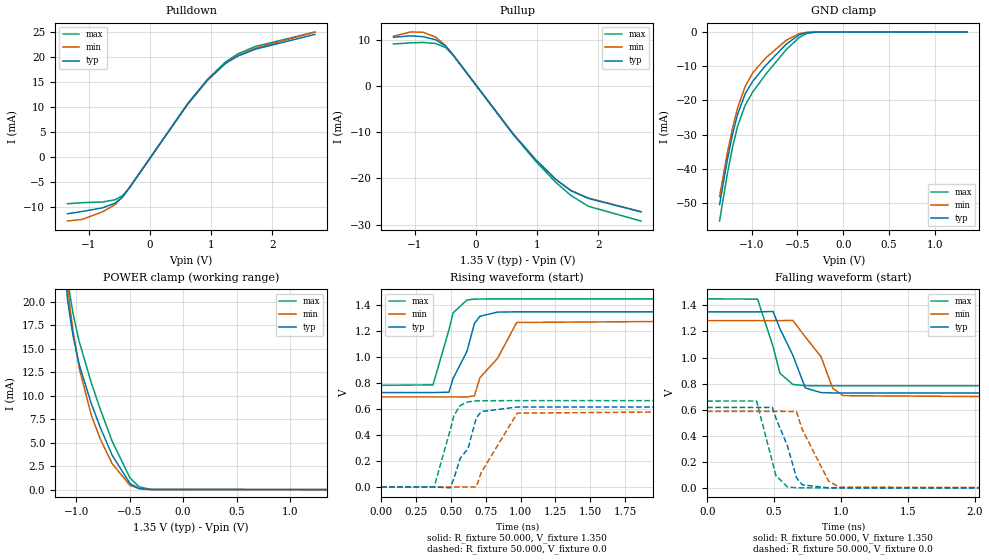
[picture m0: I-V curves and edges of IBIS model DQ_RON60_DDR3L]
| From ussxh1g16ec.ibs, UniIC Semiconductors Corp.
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|   Model DQ_RON60_DDR3L
[Model] DQ_RON60_DDR3L
Model_type I/O
Vinl =  0.540V
Vinh =  0.810V
Vmeas =  0.675V
Rref =  50.000
Vref =  0.675V
C_comp   1.224pF   1.223pF   1.239pF
[Model Spec]
Vinh   0.810V   0.776V   0.860V
Vinl   0.540V   0.506V   0.590V
Vmeas   0.675V   0.641V   0.725V
Vref   0.675V   0.641V   0.725V
Rref   50.000   NA   NA
[Temperature Range]   25.000   95.000   0.0
[Voltage Range]   1.350V   1.283V   1.450V
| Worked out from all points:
|   slope of the pulldown table from 0 to 0.203 V, typ, clamps not added: 55.3 ohm
|   slope of the pullup table from 0 to 0.203 V, typ, clamps not added: 56.9 ohm
|   GND clamp passes 1 mA (typ) near -0.49 V on its own axis
|   POWER clamp passes 1 mA (typ) near -0.53 V on its own axis
|   rising waveform, R_fixture 50.000, V_fixture 1.350: 20-80 % time 138ps typ, 185ps min, 108ps max; typ from 0.728 V to 1.35 V
|   rising waveform, R_fixture 50.000, V_fixture 0.0: 20-80 % time 132ps typ, 176ps min, 106ps max; typ from 0 V to 0.617 V
|   falling waveform, R_fixture 50.000, V_fixture 1.350: 20-80 % time 140ps typ, 184ps min, 112ps max; typ from 1.35 V to 0.728 V
|   falling waveform, R_fixture 50.000, V_fixture 0.0: 20-80 % time 129ps typ, 172ps min, 102ps max; typ from 0.617 V to 0 V
[Pulldown]
|Voltage   I(typ)   I(min)   I(max)
-1.35V    -11.32mA   -12.77mA   -9.304mA
-1.104V   -10.85mA   -12.43mA   -9.089mA
-776mV    -10.13mA   -10.93mA   -8.962mA
-571mV    -9.195mA   -9.485mA   -8.51mA
-448mV    -7.97mA    -7.94mA    -7.687mA
-325mV    -5.951mA   -5.848mA   -5.943mA
618mV     10.72mA    10.58mA    10.76mA
946mV     15.57mA    15.46mA    15.67mA
1.233V    18.79mA    18.79mA    19.06mA
1.438V    20.27mA    20.37mA    20.72mA
1.725V    21.65mA    21.85mA    22.2mA
2.7V      24.61mA    25.09mA    25.08mA
[Pullup]
|Voltage   I(typ)   I(min)   I(max)
-1.35V    10.58mA    10.79mA    9.127mA
-1.072V   10.88mA    11.71mA    9.364mA
-867mV    10.71mA    11.67mA    9.453mA
-662mV    10.05mA    10.62mA    9.234mA
-498mV    8.669mA    8.808mA    8.342mA
-375mV    6.743mA    6.763mA    6.718mA
609mV     -10.37mA   -10.35mA   -10.49mA
978mV     -15.98mA   -15.95mA   -16.28mA
1.306V    -20.22mA   -20.19mA   -20.83mA
1.552V    -22.64mA   -22.59mA   -23.67mA
1.839V    -24.32mA   -24.24mA   -26.02mA
2.7V      -27.24mA   -27.18mA   -29.21mA
[GND_clamp]
|Voltage   I(typ)   I(min)   I(max)
-1.35V    -50.46mA   -48.12mA   -55.26mA
-1.266V   -37.47mA   -35.5mA    -41.62mA
-1.21V    -30.09mA   -28.26mA   -33.85mA
-1.154V   -24.12mA   -22.27mA   -27.6mA
-1.07V    -18.03mA   -15.85mA   -21.35mA
-986mV    -14.32mA   -11.87mA   -17.45mA
-846mV    -9.744mA   -7.556mA   -12.34mA
-622mV    -3.532mA   -2.404mA   -5.117mA
-482mV    -818.9uA   -469.6uA   -1.603mA
-398mV    -151.1uA   -90.66uA   -406.2uA
-286mV    -6.358uA   -5.844uA   -20.22uA
1.35V     0A         0A         0A
[POWER_clamp]
|Voltage   I(typ)   I(min)   I(max)
-1.35V    60.76mA    63.05mA    63.71mA
-1.086V   20.55mA    21.97mA    22.81mA
-1.058V   18.21mA    19.18mA    20.54mA
-1.03V    16.29mA    16.77mA    18.67mA
-974mV    13.34mA    12.95mA    15.78mA
-862mV    9.205mA    7.993mA    11.44mA
-778mV    6.661mA    5.422mA    8.61mA
-666mV    3.683mA    2.783mA    5.175mA
-498mV    635.5uA    452.4uA    1.24mA
-414mV    119.3uA    100.7uA    293.8uA
-302mV    5.933uA    8.44uA     15.23uA
1.35V     0A         0A         0A
[Ramp]
| variable   typ   min   max
dV/dt_r   0.370/0.132n   0.352/0.176n   0.399/0.106n
dV/dt_f   0.373/0.140n   0.353/0.184n   0.400/0.112n
R_load = 50.000
[Rising Waveform]
R_fixture= 50.000
V_fixture= 1.350
V_fixture_min= 1.283
V_fixture_max= 1.450
|time   V(typ)   V(min)   V(max)
0s        727.9mV    694.2mV    783.2mV
372ps     727.9mV    694.2mV    787.2mV
486ps     730.6mV    694.2mV    1.21V
516ps     836.3mV    694.3mV    1.342V
615ps     1.044V     693.8mV    1.441V
669ps     1.26V      702.7mV    1.448V
708ps     1.316V     841.9mV    1.449V
835ps     1.348V     991.8mV    1.45V
972ps     1.35V      1.268V     1.45V
3ns       1.35V      1.283V     1.45V
[Rising Waveform]
R_fixture= 50.000
V_fixture= 0.0
V_fixture_min= 0.0
V_fixture_max= 0.0
|time   V(typ)   V(min)   V(max)
0s        129nV      580.1nV    215nV
380ps     -21.31uV   6.969uV    -8.933uV
495ps     -6.806mV   288.3nV    437.4mV
522ps     65.64mV    -19.91uV   550.9mV
567ps     221.1mV    101.6uV    628.1mV
623ps     295.3mV    419.1uV    656mV
682ps     531.8mV    -149.2uV   663.3mV
718ps     581mV      112.2mV    664.7mV
976ps     616.5mV    569.2mV    665.7mV
3ns       616.6mV    586.6mV    665.7mV
[Falling Waveform]
R_fixture= 50.000
V_fixture= 1.350
V_fixture_min= 1.283
V_fixture_max= 1.450
|time   V(typ)   V(min)   V(max)
0s        1.35V      1.283V     1.45V
377ps     1.35V      1.283V     1.448V
493ps     1.353V     1.283V     1.082V
544ps     1.221V     1.283V     879.3mV
640ps     1.019V     1.285V     793.5mV
734ps     766.1mV    1.158V     784.3mV
852ps     730.8mV    1.005V     783.3mV
938ps     728.4mV    764.5mV    783.2mV
1.018ns   728mV      707.3mV    783.2mV
3ns       727.9mV    694.2mV    783.2mV
[Falling Waveform]
R_fixture= 50.000
V_fixture= 0.0
V_fixture_min= 0.0
V_fixture_max= 0.0
|time   V(typ)   V(min)   V(max)
0s        616.6mV    586.6mV    665.7mV
369ps     616.6mV    586.6mV    666.4mV
487ps     617.3mV    586.6mV    200.8mV
514ps     534.5mV    586.6mV    93.93mV
600ps     322.3mV    586.6mV    7.097mV
668ps     77.81mV    583.8mV    894.8uV
710ps     23.2mV     450mV      248.9uV
908ps     65.67uV    51.07mV    997.6nV
991ps     5.847uV    5.241mV    472.2nV
3ns       294.5nV    649.8nV    404.2nV
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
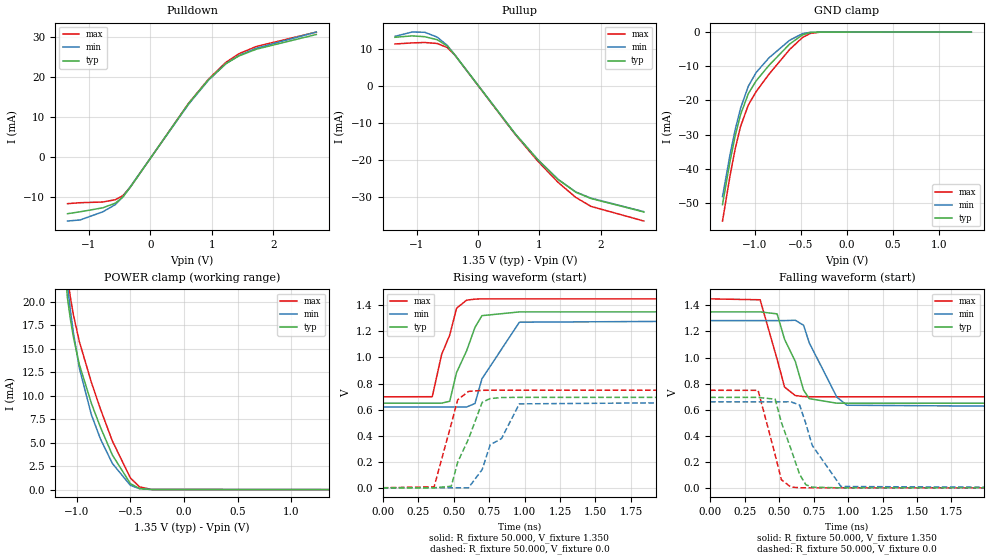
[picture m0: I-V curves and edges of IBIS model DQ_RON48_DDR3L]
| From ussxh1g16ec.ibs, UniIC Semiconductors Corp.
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|   Model DQ_RON48_DDR3L
[Model] DQ_RON48_DDR3L
Model_type I/O
Vinl =  0.540V
Vinh =  0.810V
Vmeas =  0.675V
Rref =  50.000
Vref =  0.675V
C_comp   1.224pF   1.223pF   1.239pF
[Model Spec]
Vinh   0.810V   0.776V   0.860V
Vinl   0.540V   0.506V   0.590V
Vmeas   0.675V   0.641V   0.725V
Vref   0.675V   0.641V   0.725V
Rref   50.000   NA   NA
[Temperature Range]   25.000   95.000   0.0
[Voltage Range]   1.350V   1.283V   1.450V
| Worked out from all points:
|   slope of the pulldown table from 0 to 0.203 V, typ, clamps not added: 44.3 ohm
|   slope of the pullup table from 0 to 0.203 V, typ, clamps not added: 45.6 ohm
|   GND clamp passes 1 mA (typ) near -0.49 V on its own axis
|   POWER clamp passes 1 mA (typ) near -0.53 V on its own axis
|   rising waveform, R_fixture 50.000, V_fixture 1.350: 20-80 % time 140ps typ, 190ps min, 109ps max; typ from 0.649 V to 1.35 V
|   rising waveform, R_fixture 50.000, V_fixture 0.0: 20-80 % time 136ps typ, 182ps min, 107ps max; typ from 0 V to 0.694 V
|   falling waveform, R_fixture 50.000, V_fixture 1.350: 20-80 % time 141ps typ, 188ps min, 111ps max; typ from 1.35 V to 0.649 V
|   falling waveform, R_fixture 50.000, V_fixture 0.0: 20-80 % time 132ps typ, 178ps min, 102ps max; typ from 0.694 V to 0 V
[Pulldown]
|Voltage   I(typ)   I(min)   I(max)
-1.35V    -14.13mA   -15.96mA   -11.62mA
-1.145V   -13.65mA   -15.7mA    -11.38mA
-776mV    -12.66mA   -13.66mA   -11.2mA
-571mV    -11.49mA   -11.85mA   -10.63mA
-448mV    -9.956mA   -9.918mA   -9.604mA
-325mV    -7.433mA   -7.305mA   -7.423mA
618mV     13.39mA    13.21mA    13.45mA
946mV     19.45mA    19.31mA    19.57mA
1.233V    23.48mA    23.48mA    23.82mA
1.438V    25.33mA    25.45mA    25.89mA
1.725V    27.05mA    27.3mA     27.73mA
2.7V      30.73mA    31.34mA    31.32mA
[Pullup]
|Voltage   I(typ)   I(min)   I(max)
-1.35V    13.22mA    13.48mA    11.41mA
-1.072V   13.6mA     14.64mA    11.7mA
-867mV    13.38mA    14.58mA    11.81mA
-662mV    12.56mA    13.26mA    11.54mA
-498mV    10.83mA    11mA       10.42mA
-375mV    8.421mA    8.445mA    8.39mA
609mV     -12.94mA   -12.92mA   -13.1mA
978mV     -19.95mA   -19.92mA   -20.33mA
1.306V    -25.26mA   -25.21mA   -26.02mA
1.593V    -28.67mA   -28.6mA    -30.07mA
1.839V    -30.36mA   -30.26mA   -32.49mA
2.7V      -34mA      -33.92mA   -36.45mA
[GND_clamp]
|Voltage   I(typ)   I(min)   I(max)
-1.35V    -50.46mA   -48.12mA   -55.26mA
-1.266V   -37.47mA   -35.5mA    -41.62mA
-1.21V    -30.09mA   -28.26mA   -33.85mA
-1.154V   -24.12mA   -22.27mA   -27.6mA
-1.07V    -18.03mA   -15.85mA   -21.35mA
-986mV    -14.32mA   -11.87mA   -17.45mA
-846mV    -9.744mA   -7.556mA   -12.34mA
-622mV    -3.532mA   -2.404mA   -5.117mA
-482mV    -818.9uA   -469.6uA   -1.603mA
-398mV    -151.1uA   -90.66uA   -406.2uA
-286mV    -6.358uA   -5.844uA   -20.22uA
1.35V     0A         0A         0A
[POWER_clamp]
|Voltage   I(typ)   I(min)   I(max)
-1.35V    60.76mA    63.05mA    63.71mA
-1.086V   20.55mA    21.97mA    22.81mA
-1.058V   18.21mA    19.18mA    20.54mA
-1.03V    16.29mA    16.77mA    18.67mA
-974mV    13.34mA    12.95mA    15.78mA
-862mV    9.205mA    7.993mA    11.44mA
-778mV    6.661mA    5.422mA    8.61mA
-666mV    3.683mA    2.783mA    5.175mA
-498mV    635.5uA    452.4uA    1.24mA
-414mV    119.3uA    100.7uA    293.8uA
-302mV    5.933uA    8.44uA     15.23uA
1.35V     0A         0A         0A
[Ramp]
| variable   typ   min   max
dV/dt_r   0.416/0.135n   0.396/0.182n   0.449/0.107n
dV/dt_f   0.420/0.141n   0.398/0.187n   0.451/0.111n
R_load = 50.000
[Rising Waveform]
R_fixture= 50.000
V_fixture= 1.350
V_fixture_min= 1.283
V_fixture_max= 1.450
|time   V(typ)   V(min)   V(max)
0s        649.3mV    620.2mV    698.3mV
350ps     649.3mV    620.2mV    698.9mV
416ps     649.5mV    620.2mV    1.023V
473ps     664mV      620.2mV    1.172V
521ps     883.8mV    620.3mV    1.378V
592ps     1.051V     619.8mV    1.44V
651ps     1.231V     646.6mV    1.448V
700ps     1.321V     836.4mV    1.45V
964ps     1.35V      1.271V     1.45V
3ns       1.35V      1.283V     1.45V
[Rising Waveform]
R_fixture= 50.000
V_fixture= 0.0
V_fixture_min= 0.0
V_fixture_max= 0.0
|time   V(typ)   V(min)   V(max)
0s        115.5nV    519nV      192.4nV
363ps     -23.09uV   7.135uV    7.2mV
484ps     11.36mV    -4.386uV   489.9mV
529ps     195.8mV    10.29uV    675mV
605ps     373.4mV    -694.1uV   739.3mV
702ps     656.5mV    140.4mV    748mV
758ps     684.8mV    330.5mV    748.6mV
838ps     692.6mV    377.4mV    748.7mV
963ps     694mV      644mV      748.7mV
3ns       694mV      660mV      748.7mV
[Falling Waveform]
R_fixture= 50.000
V_fixture= 1.350
V_fixture_min= 1.283
V_fixture_max= 1.450
|time   V(typ)   V(min)   V(max)
0s        1.35V      1.283V     1.45V
363ps     1.35V      1.283V     1.443V
486ps     1.335V     1.283V     987.2mV
540ps     1.14V      1.283V     773.2mV
618ps     969.4mV    1.286V     708.1mV
678ps     749.3mV    1.247V     700.4mV
719ps     684.3mV    1.113V     699mV
919ps     649.6mV    696.1mV    698.3mV
992ps     649.3mV    633.9mV    698.3mV
3ns       649.3mV    620.2mV    698.3mV
[Falling Waveform]
R_fixture= 50.000
V_fixture= 0.0
V_fixture_min= 0.0
V_fixture_max= 0.0
|time   V(typ)   V(min)   V(max)
0s        694mV      660mV      748.7mV
348ps     694mV      660mV      748mV
472ps     680.1mV    660mV      252.4mV
517ps     501.6mV    659.9mV    62.21mV
585ps     302mV      660.3mV    6.263mV
649ps     103.7mV    635.7mV    687.5uV
694ps     24.33mV    493.2mV    146.6uV
741ps     5.176mV    325.1mV    28.71uV
949ps     5.542uV    10.33mV    366.5nV
3ns       236nV      593.6nV    311.5nV
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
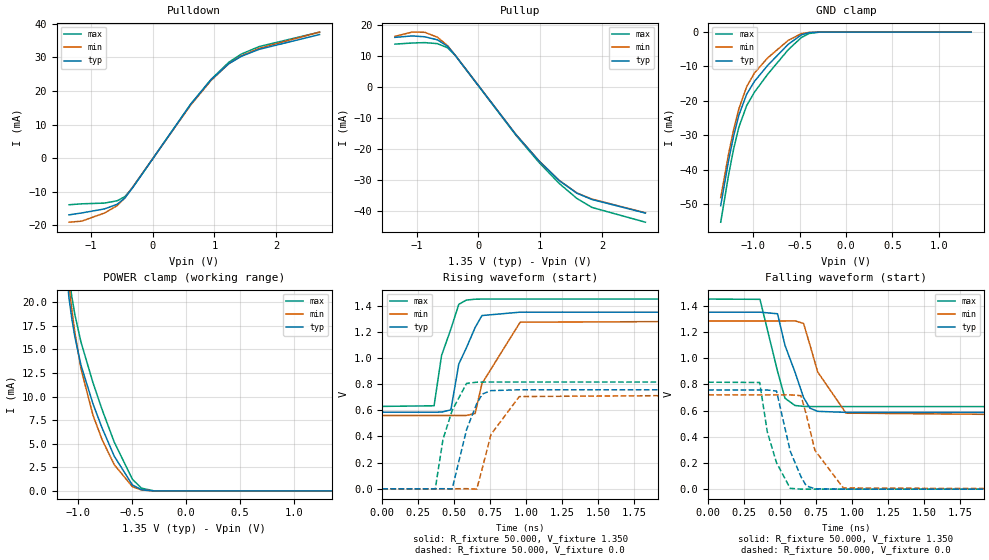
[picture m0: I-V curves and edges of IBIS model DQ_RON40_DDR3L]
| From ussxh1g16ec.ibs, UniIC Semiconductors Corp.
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|   Model DQ_RON40_DDR3L
[Model] DQ_RON40_DDR3L
Model_type I/O
Vinl =  0.540V
Vinh =  0.810V
Vmeas =  0.675V
Rref =  50.000
Vref =  0.675V
C_comp   1.224pF   1.223pF   1.239pF
[Model Spec]
Vinh   0.810V   0.776V   0.860V
Vinl   0.540V   0.506V   0.590V
Vmeas   0.675V   0.641V   0.725V
Vref   0.675V   0.641V   0.725V
Rref   50.000   NA   NA
[Temperature Range]   25.000   95.000   0.0
[Voltage Range]   1.350V   1.283V   1.450V
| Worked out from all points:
|   slope of the pulldown table from 0 to 0.203 V, typ, clamps not added: 36.9 ohm
|   slope of the pullup table from 0 to 0.203 V, typ, clamps not added: 38 ohm
|   GND clamp passes 1 mA (typ) near -0.49 V on its own axis
|   POWER clamp passes 1 mA (typ) near -0.53 V on its own axis
|   rising waveform, R_fixture 50.000, V_fixture 1.350: 20-80 % time 135ps typ, 187ps min, 104ps max; typ from 0.586 V to 1.35 V
|   rising waveform, R_fixture 50.000, V_fixture 0.0: 20-80 % time 130ps typ, 179ps min, 102ps max; typ from 0 V to 0.757 V
|   falling waveform, R_fixture 50.000, V_fixture 1.350: 20-80 % time 136ps typ, 183ps min, 105ps max; typ from 1.35 V to 0.586 V
|   falling waveform, R_fixture 50.000, V_fixture 0.0: 20-80 % time 127ps typ, 172ps min, 96.9ps max; typ from 0.757 V to 0 V
[Pulldown]
|Voltage   I(typ)   I(min)   I(max)
-1.35V    -16.95mA   -19.14mA   -13.94mA
-1.145V   -16.38mA   -18.83mA   -13.66mA
-776mV    -15.18mA   -16.39mA   -13.44mA
-571mV    -13.78mA   -14.21mA   -12.75mA
-448mV    -11.94mA   -11.89mA   -11.52mA
-325mV    -8.911mA   -8.758mA   -8.9mA
618mV     16.06mA    15.84mA    16.12mA
946mV     23.33mA    23.15mA    23.47mA
1.233V    28.15mA    28.15mA    28.56mA
1.438V    30.37mA    30.51mA    31.04mA
1.725V    32.43mA    32.73mA    33.26mA
2.7V      36.84mA    37.57mA    37.56mA
[Pullup]
|Voltage   I(typ)   I(min)   I(max)
-1.35V    15.86mA    16.17mA    13.68mA
-1.072V   16.32mA    17.56mA    14.04mA
-867mV    16.05mA    17.49mA    14.17mA
-662mV    15.06mA    15.91mA    13.84mA
-498mV    12.98mA    13.19mA    12.49mA
-375mV    10.1mA     10.12mA    10.06mA
609mV     -15.52mA   -15.49mA   -15.71mA
978mV     -23.92mA   -23.88mA   -24.38mA
1.306V    -30.28mA   -30.22mA   -31.19mA
1.593V    -34.36mA   -34.28mA   -36.05mA
1.839V    -36.39mA   -36.26mA   -38.95mA
2.7V      -40.75mA   -40.65mA   -43.69mA
[GND_clamp]
|Voltage   I(typ)   I(min)   I(max)
-1.35V    -50.46mA   -48.12mA   -55.26mA
-1.266V   -37.47mA   -35.5mA    -41.62mA
-1.21V    -30.09mA   -28.26mA   -33.85mA
-1.154V   -24.12mA   -22.27mA   -27.6mA
-1.07V    -18.03mA   -15.85mA   -21.35mA
-986mV    -14.32mA   -11.87mA   -17.45mA
-846mV    -9.744mA   -7.556mA   -12.34mA
-622mV    -3.532mA   -2.404mA   -5.117mA
-482mV    -818.9uA   -469.6uA   -1.603mA
-398mV    -151.1uA   -90.66uA   -406.2uA
-286mV    -6.358uA   -5.844uA   -20.22uA
1.35V     0A         0A         0A
[POWER_clamp]
|Voltage   I(typ)   I(min)   I(max)
-1.35V    60.76mA    63.05mA    63.71mA
-1.086V   20.55mA    21.97mA    22.81mA
-1.058V   18.21mA    19.18mA    20.54mA
-1.03V    16.29mA    16.77mA    18.67mA
-974mV    13.34mA    12.95mA    15.78mA
-862mV    9.205mA    7.993mA    11.44mA
-778mV    6.661mA    5.422mA    8.61mA
-666mV    3.683mA    2.783mA    5.175mA
-498mV    635.5uA    452.4uA    1.24mA
-414mV    119.3uA    100.7uA    293.8uA
-302mV    5.933uA    8.44uA     15.23uA
1.35V     0A         0A         0A
[Ramp]
| variable   typ   min   max
dV/dt_r   0.454/0.131n   0.432/0.179n   0.490/0.101n
dV/dt_f   0.458/0.136n   0.434/0.182n   0.492/0.105n
R_load = 50.000
[Rising Waveform]
R_fixture= 50.000
V_fixture= 1.350
V_fixture_min= 1.283
V_fixture_max= 1.450
|time   V(typ)   V(min)   V(max)
0s        585.8mV    560.4mV    629.8mV
360ps     585.9mV    560.4mV    634.4mV
412ps     586.1mV    560.4mV    1.019V
477ps     603.3mV    560.4mV    1.221V
532ps     953.6mV    560.5mV    1.41V
584ps     1.075V     560.5mV    1.442V
646ps     1.233V     575.2mV    1.449V
693ps     1.324V     803.8mV    1.45V
959ps     1.35V      1.273V     1.45V
3ns       1.35V      1.283V     1.45V
[Rising Waveform]
R_fixture= 50.000
V_fixture= 0.0
V_fixture_min= 0.0
V_fixture_max= 0.0
|time   V(typ)   V(min)   V(max)
0s        104.7nV    469.8nV    174.3nV
368ps     -28.81uV   9.445uV    -1.909mV
422ps     756.9uV    20.42uV    378.1mV
486ps     -644.3uV   -9.863uV   599.6mV
586ps     451.6mV    993.3uV    805.5mV
657ps     651.1mV    -2.78mV    814.7mV
696ps     724.1mV    158.5mV    815.6mV
756ps     750.3mV    415.1mV    815.9mV
953ps     756.8mV    704.9mV    816mV
3ns       756.8mV    719.5mV    816mV
[Falling Waveform]
R_fixture= 50.000
V_fixture= 1.350
V_fixture_min= 1.283
V_fixture_max= 1.450
|time   V(typ)   V(min)   V(max)
0s        1.35V      1.283V     1.45V
360ps     1.35V      1.283V     1.448V
482ps     1.338V     1.283V     899.7mV
534ps     1.097V     1.283V     693.4mV
603ps     894.6mV    1.284V     638.5mV
663ps     699.4mV    1.264V     631.4mV
707ps     618.5mV    1.102V     630.2mV
761ps     593.6mV    894.8mV    629.9mV
958ps     585.9mV    580.1mV    629.8mV
3ns       585.8mV    560.4mV    629.8mV
[Falling Waveform]
R_fixture= 50.000
V_fixture= 0.0
V_fixture_min= 0.0
V_fixture_max= 0.0
|time   V(typ)   V(min)   V(max)
0s        756.8mV    719.5mV    816mV
358ps     756.8mV    719.5mV    813.7mV
411ps     756.4mV    719.5mV    436.5mV
475ps     748.4mV    719.5mV    202.3mV
570ps     291.4mV    719.1mV    6.196mV
645ps     94.85mV    713.2mV    355.2uV
682ps     25.38mV    569.7mV    85.38uV
742ps     2.868mV    296.6mV    8.63uV
940ps     2.196uV    8.911mV    308.6nV
3ns       188.4nV    552.7nV    259.4nV
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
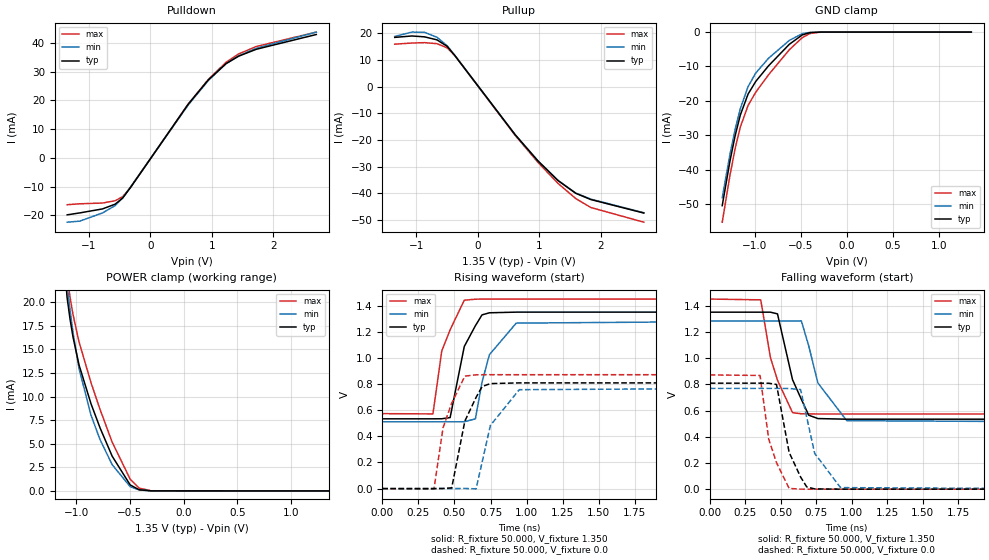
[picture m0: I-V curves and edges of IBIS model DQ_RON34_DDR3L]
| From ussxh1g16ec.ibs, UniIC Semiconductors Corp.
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|   Model DQ_RON34_DDR3L
[Model] DQ_RON34_DDR3L
Model_type I/O
Vinl =  0.540V
Vinh =  0.810V
Vmeas =  0.675V
Rref =  50.000
Vref =  0.675V
C_comp   1.224pF   1.223pF   1.239pF
[Model Spec]
Vinh   0.810V   0.776V   0.860V
Vinl   0.540V   0.506V   0.590V
Vmeas   0.675V   0.641V   0.725V
Vref   0.675V   0.641V   0.725V
Rref   50.000   NA   NA
[Temperature Range]   25.000   95.000   0.0
[Voltage Range]   1.350V   1.283V   1.450V
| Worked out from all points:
|   slope of the pulldown table from 0 to 0.203 V, typ, clamps not added: 31.7 ohm
|   slope of the pullup table from 0 to 0.203 V, typ, clamps not added: 32.6 ohm
|   GND clamp passes 1 mA (typ) near -0.49 V on its own axis
|   POWER clamp passes 1 mA (typ) near -0.53 V on its own axis
|   rising waveform, R_fixture 50.000, V_fixture 1.350: 20-80 % time 134ps typ, 186ps min, 102ps max; typ from 0.534 V to 1.35 V
|   rising waveform, R_fixture 50.000, V_fixture 0.0: 20-80 % time 130ps typ, 180ps min, 101ps max; typ from 0 V to 0.809 V
|   falling waveform, R_fixture 50.000, V_fixture 1.350: 20-80 % time 133ps typ, 179ps min, 102ps max; typ from 1.35 V to 0.534 V
|   falling waveform, R_fixture 50.000, V_fixture 0.0: 20-80 % time 125ps typ, 170ps min, 95ps max; typ from 0.809 V to 0 V
[Pulldown]
|Voltage   I(typ)   I(min)   I(max)
-1.35V    -19.77mA   -22.33mA   -16.25mA
-1.145V   -19.1mA    -21.96mA   -15.93mA
-776mV    -17.71mA   -19.11mA   -15.67mA
-571mV    -16.07mA   -16.57mA   -14.87mA
-448mV    -13.92mA   -13.86mA   -13.43mA
-325mV    -10.39mA   -10.21mA   -10.37mA
618mV     18.72mA    18.46mA    18.79mA
946mV     27.19mA    26.98mA    27.35mA
1.233V    32.82mA    32.81mA    33.29mA
1.438V    35.41mA    35.57mA    36.19mA
1.725V    37.81mA    38.16mA    38.77mA
2.7V      42.94mA    43.78mA    43.78mA
[Pullup]
|Voltage   I(typ)   I(min)   I(max)
-1.35V    18.5mA     18.86mA    15.96mA
-1.072V   19.03mA    20.49mA    16.37mA
-867mV    18.71mA    20.4mA     16.53mA
-662mV    17.56mA    18.54mA    16.14mA
-498mV    15.13mA    15.37mA    14.57mA
-375mV    11.76mA    11.8mA     11.72mA
609mV     -18.08mA   -18.05mA   -18.3mA
978mV     -27.87mA   -27.82mA   -28.4mA
1.306V    -35.28mA   -35.21mA   -36.34mA
1.593V    -40.04mA   -39.94mA   -42mA
1.839V    -42.39mA   -42.24mA   -45.38mA
2.7V      -47.46mA   -47.34mA   -50.89mA
[GND_clamp]
|Voltage   I(typ)   I(min)   I(max)
-1.35V    -50.46mA   -48.12mA   -55.26mA
-1.266V   -37.47mA   -35.5mA    -41.62mA
-1.21V    -30.09mA   -28.26mA   -33.85mA
-1.154V   -24.12mA   -22.27mA   -27.6mA
-1.07V    -18.03mA   -15.85mA   -21.35mA
-986mV    -14.32mA   -11.87mA   -17.45mA
-846mV    -9.744mA   -7.556mA   -12.34mA
-622mV    -3.532mA   -2.404mA   -5.117mA
-482mV    -818.9uA   -469.6uA   -1.603mA
-398mV    -151.1uA   -90.66uA   -406.2uA
-286mV    -6.358uA   -5.844uA   -20.22uA
1.35V     0A         0A         0A
[POWER_clamp]
|Voltage   I(typ)   I(min)   I(max)
-1.35V    60.76mA    63.05mA    63.71mA
-1.086V   20.55mA    21.97mA    22.81mA
-1.058V   18.21mA    19.18mA    20.54mA
-1.03V    16.29mA    16.77mA    18.67mA
-974mV    13.34mA    12.95mA    15.78mA
-862mV    9.205mA    7.993mA    11.44mA
-778mV    6.661mA    5.422mA    8.61mA
-666mV    3.683mA    2.783mA    5.175mA
-498mV    635.5uA    452.4uA    1.24mA
-414mV    119.3uA    100.7uA    293.8uA
-302mV    5.933uA    8.44uA     15.23uA
1.35V     0A         0A         0A
[Ramp]
| variable   typ   min   max
dV/dt_r   0.485/0.130n   0.461/0.180n   0.523/0.101n
dV/dt_f   0.490/0.132n   0.463/0.179n   0.526/0.102n
R_load = 50.000
[Rising Waveform]
R_fixture= 50.000
V_fixture= 1.350
V_fixture_min= 1.283
V_fixture_max= 1.450
|time   V(typ)   V(min)   V(max)
0s        533.7mV    511.1mV    573.5mV
351ps     533.7mV    511.1mV    571.3mV
412ps     534.2mV    511.1mV    1.052V
470ps     543.2mV    511.1mV    1.215V
568ps     1.087V     511.5mV    1.441V
645ps     1.246V     533.2mV    1.449V
691ps     1.329V     814.6mV    1.45V
742ps     1.345V     1.024V     1.45V
928ps     1.35V      1.266V     1.45V
3ns       1.35V      1.283V     1.45V
[Rising Waveform]
R_fixture= 50.000
V_fixture= 0.0
V_fixture_min= 0.0
V_fixture_max= 0.0
|time   V(typ)   V(min)   V(max)
0s        95.71nV    429.1nV    159.3nV
358ps     -30.16uV   9.754uV    -4.423mV
421ps     994.6uV    24.02uV    465.5mV
481ps     5.491mV    -12.84uV   653.8mV
572ps     516.5mV    1.055mV    860.6mV
650ps     698.3mV    -2.048mV   870.5mV
692ps     781.1mV    204.1mV    871.2mV
749ps     803.3mV    483.1mV    871.4mV
949ps     808.6mV    756.8mV    871.5mV
3ns       808.6mV    768.6mV    871.5mV
[Falling Waveform]
R_fixture= 50.000
V_fixture= 1.350
V_fixture_min= 1.283
V_fixture_max= 1.450
|time   V(typ)   V(min)   V(max)
0s        1.35V      1.283V     1.45V
359ps     1.35V      1.283V     1.444V
427ps     1.35V      1.283V     1.005V
477ps     1.337V     1.283V     831.1mV
583ps     835.1mV    1.282V     583.4mV
645ps     685.3mV    1.284V     575mV
697ps     564.3mV    1.093V     573.8mV
762ps     538.5mV    809.5mV    573.5mV
965ps     533.7mV    522.4mV    573.5mV
3ns       533.7mV    511.1mV    573.5mV
[Falling Waveform]
R_fixture= 50.000
V_fixture= 0.0
V_fixture_min= 0.0
V_fixture_max= 0.0
|time   V(typ)   V(min)   V(max)
0s        808.6mV    768.6mV    871.5mV
354ps     808.6mV    768.6mV    867.2mV
415ps     808.1mV    768.6mV    382.4mV
470ps     798.7mV    768.6mV    202.4mV
559ps     280.7mV    768.1mV    5.814mV
640ps     92.41mV    759.8mV    192.4uV
683ps     17.32mV    547.7mV    31.13uV
739ps     1.855mV    273.1mV    3.189uV
921ps     1.535uV    11.85mV    263.4nV
3ns       -34.23nV   492.4nV    203nV
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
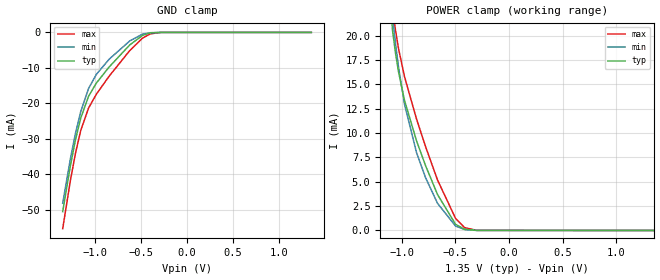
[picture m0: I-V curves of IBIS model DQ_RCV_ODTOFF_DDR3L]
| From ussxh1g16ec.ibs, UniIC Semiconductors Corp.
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|   Model DQ_RCV_ODTOFF_DDR3L
[Model] DQ_RCV_ODTOFF_DDR3L
Model_type Input
Vinl =  0.540V
Vinh =  0.810V
C_comp   1.224pF   1.223pF   1.239pF
[Model Spec]
Vinh   0.810V   0.776V   0.860V
Vinl   0.540V   0.506V   0.590V
[Temperature Range]   25.000   95.000   0.0
[Voltage Range]   1.350V   1.283V   1.450V
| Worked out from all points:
|   GND clamp passes 1 mA (typ) near -0.49 V on its own axis
|   POWER clamp passes 1 mA (typ) near -0.53 V on its own axis
[GND_clamp]
|Voltage   I(typ)   I(min)   I(max)
-1.35V    -50.46mA   -48.12mA   -55.26mA
-1.266V   -37.47mA   -35.5mA    -41.62mA
-1.21V    -30.09mA   -28.26mA   -33.85mA
-1.154V   -24.12mA   -22.27mA   -27.6mA
-1.07V    -18.03mA   -15.85mA   -21.35mA
-986mV    -14.32mA   -11.87mA   -17.45mA
-846mV    -9.744mA   -7.556mA   -12.34mA
-622mV    -3.532mA   -2.404mA   -5.117mA
-482mV    -818.9uA   -469.6uA   -1.603mA
-398mV    -151.1uA   -90.66uA   -406.2uA
-286mV    -6.358uA   -5.844uA   -20.22uA
1.35V     0A         0A         0A
[POWER_clamp]
|Voltage   I(typ)   I(min)   I(max)
-1.35V    60.76mA    63.05mA    63.71mA
-1.086V   20.55mA    21.97mA    22.81mA
-1.058V   18.21mA    19.18mA    20.54mA
-1.03V    16.29mA    16.77mA    18.67mA
-974mV    13.34mA    12.95mA    15.78mA
-862mV    9.205mA    7.993mA    11.44mA
-778mV    6.661mA    5.422mA    8.61mA
-666mV    3.683mA    2.783mA    5.175mA
-498mV    635.5uA    452.4uA    1.24mA
-414mV    119.3uA    100.7uA    293.8uA
-302mV    5.933uA    8.44uA     15.23uA
1.35V     0A         0A         0A
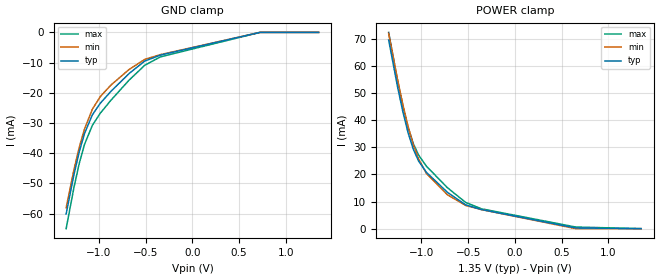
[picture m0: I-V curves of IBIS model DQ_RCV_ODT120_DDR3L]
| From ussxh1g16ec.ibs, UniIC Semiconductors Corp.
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|   Model DQ_RCV_ODT120_DDR3L
[Model] DQ_RCV_ODT120_DDR3L
Model_type Input
Vinl =  0.540V
Vinh =  0.810V
C_comp   1.224pF   1.223pF   1.239pF
[Model Spec]
Vinh   0.810V   0.776V   0.860V
Vinl   0.540V   0.506V   0.590V
[Temperature Range]   25.000   95.000   0.0
[Voltage Range]   1.350V   1.283V   1.450V
[GND_clamp]
|Voltage   I(typ)   I(min)   I(max)
-1.35V    -60.1mA    -58.06mA   -64.97mA
-1.266V   -47.01mA   -45.36mA   -51.24mA
-1.21V    -39.55mA   -38.07mA   -43.4mA
-1.154V   -33.5mA    -32mA      -37.1mA
-1.07V    -27.31mA   -25.44mA   -30.78mA
-986mV    -23.49mA   -21.3mA    -26.8mA
-874mV    -19.62mA   -17.52mA   -22.56mA
-678mV    -13.65mA   -12.3mA    -15.84mA
-510mV    -9.504mA   -8.949mA   -10.9mA
-342mV    -7.51mA    -7.356mA   -8.102mA
722mV     0A         0A         -4.527uA
1.35V     0A         0A         0A
[POWER_clamp]
|Voltage   I(typ)   I(min)   I(max)
-1.35V    69.54mA    71.97mA    72.32mA
-1.254V   52.09mA    54.77mA    54.47mA
-1.198V   43.05mA    45.69mA    45.22mA
-1.142V   35.3mA     37.64mA    37.35mA
-1.086V   29.24mA    30.92mA    31.31mA
-1.03V    24.94mA    25.69mA    27.14mA
-946mV    20.75mA    20.32mA    23.01mA
-722mV    13.4mA     12.5mA     15.1mA
-526mV    8.771mA    8.539mA    9.656mA
-358mV    7.043mA    7.024mA    7.32mA
650mV     248.1uA    0A         605.7uA
1.35V     0A         0A         0A
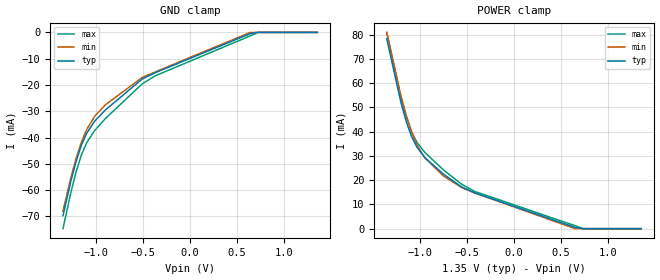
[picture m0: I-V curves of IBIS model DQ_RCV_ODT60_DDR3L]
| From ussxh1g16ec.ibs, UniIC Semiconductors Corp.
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|   Model DQ_RCV_ODT60_DDR3L
[Model] DQ_RCV_ODT60_DDR3L
Model_type Input
Vinl =  0.540V
Vinh =  0.810V
C_comp   1.224pF   1.223pF   1.239pF
[Model Spec]
Vinh   0.810V   0.776V   0.860V
Vinl   0.540V   0.506V   0.590V
[Temperature Range]   25.000   95.000   0.0
[Voltage Range]   1.350V   1.283V   1.450V
[GND_clamp]
|Voltage   I(typ)   I(min)   I(max)
-1.35V    -69.73mA   -67.99mA   -74.67mA
-1.266V   -56.53mA   -55.22mA   -60.85mA
-1.21V    -49.01mA   -47.86mA   -52.96mA
-1.154V   -42.88mA   -41.72mA   -46.6mA
-1.098V   -38.33mA   -36.93mA   -41.96mA
-1.014V   -33.8mA    -31.96mA   -37.36mA
-902mV    -29.58mA   -27.62mA   -32.85mA
-510mV    -17.77mA   -17.15mA   -19.61mA
-370mV    -15.33mA   -15.03mA   -16.51mA
638mV     -478.2uA   -14.02uA   -1.331mA
722mV     0A         0A         -8.362uA
1.35V     0A         0A         0A
[POWER_clamp]
|Voltage   I(typ)   I(min)   I(max)
-1.35V    78.34mA    80.9mA     80.92mA
-1.198V   51.81mA    54.64mA    53.77mA
-1.142V   44.04mA    46.6mA     45.88mA
-1.086V   37.94mA    39.87mA    39.82mA
-1.03V    33.6mA     34.62mA    35.62mA
-946mV    29.33mA    29.18mA    31.45mA
-750mV    22.54mA    21.8mA     24.29mA
-554mV    17.17mA    16.91mA    18.29mA
-414mV    14.73mA    14.7mA     15.32mA
650mV     495.9uA    0A         1.21mA
734mV     0A         0A         0A
1.35V     0A         0A         0A
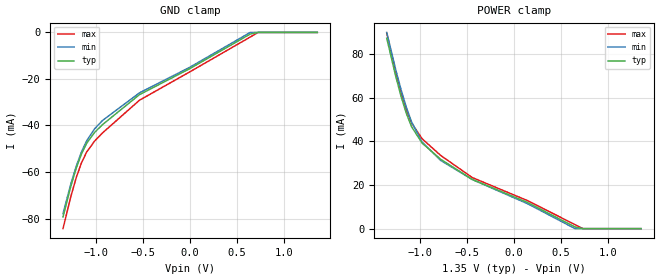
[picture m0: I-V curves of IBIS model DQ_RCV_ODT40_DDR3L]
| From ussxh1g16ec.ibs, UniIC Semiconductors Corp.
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|   Model DQ_RCV_ODT40_DDR3L
[Model] DQ_RCV_ODT40_DDR3L
Model_type Input
Vinl =  0.540V
Vinh =  0.810V
C_comp   1.224pF   1.223pF   1.239pF
[Model Spec]
Vinh   0.810V   0.776V   0.860V
Vinl   0.540V   0.506V   0.590V
[Temperature Range]   25.000   95.000   0.0
[Voltage Range]   1.350V   1.283V   1.450V
[GND_clamp]
|Voltage   I(typ)   I(min)   I(max)
-1.35V    -79.32mA   -77.88mA   -84.33mA
-1.266V   -66.02mA   -65.03mA   -70.41mA
-1.21V    -58.42mA   -57.61mA   -62.47mA
-1.154V   -52.22mA   -51.39mA   -56.05mA
-1.098V   -47.59mA   -46.52mA   -51.36mA
-1.014V   -42.96mA   -41.39mA   -46.69mA
-930mV    -39.61mA   -37.84mA   -43.18mA
-538mV    -26.75mA   -25.98mA   -29.14mA
-6mV      -15.62mA   -15.04mA   -17.01mA
638mV     -714.4uA   -19.49uA   -1.991mA
722mV     0A         0A         -11.55uA
1.35V     0A         0A         0A
[POWER_clamp]
|Voltage   I(typ)   I(min)   I(max)
-1.35V    87.11mA    89.8mA     89.51mA
-1.254V   69.63mA    72.64mA    71.6mA
-1.198V   60.55mA    63.58mA    62.3mA
-1.142V   52.75mA    55.53mA    54.38mA
-1.086V   46.61mA    48.79mA    48.3mA
-974mV    39.14mA    39.6mA     41.1mA
-778mV    31.77mA    31.24mA    33.53mA
-442mV    22.52mA    22.48mA    23.38mA
146mV     11.94mA    11.4mA     12.81mA
650mV     743.3uA    0A         1.813mA
734mV     0A         0A         0A
1.35V     0A         0A         0A
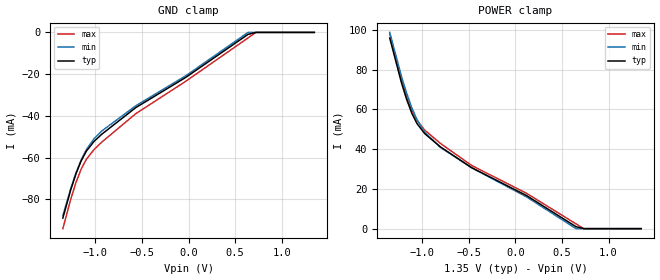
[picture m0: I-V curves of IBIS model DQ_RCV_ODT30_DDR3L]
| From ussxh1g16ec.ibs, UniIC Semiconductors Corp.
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|   Model DQ_RCV_ODT30_DDR3L
[Model] DQ_RCV_ODT30_DDR3L
Model_type Input
Vinl =  0.540V
Vinh =  0.810V
C_comp   1.224pF   1.223pF   1.239pF
[Model Spec]
Vinh   0.810V   0.776V   0.860V
Vinl   0.540V   0.506V   0.590V
[Temperature Range]   25.000   95.000   0.0
[Voltage Range]   1.350V   1.283V   1.450V
[GND_clamp]
|Voltage   I(typ)   I(min)   I(max)
-1.35V    -89.01mA   -87.86mA   -94.1mA
-1.266V   -75.6mA    -74.94mA   -80.09mA
-1.21V    -67.93mA   -67.46mA   -72.08mA
-1.154V   -61.65mA   -61.17mA   -65.61mA
-1.098V   -56.95mA   -56.2mA    -60.87mA
-1.014V   -52.21mA   -50.91mA   -56.12mA
-930mV    -48.74mA   -47.2mA    -52.53mA
-566mV    -36.03mA   -35.15mA   -38.94mA
-34mV     -21.68mA   -20.91mA   -23.55mA
638mV     -958.1uA   -29.1uA    -2.663mA
722mV     0A         0A         -18.96uA
1.35V     0A         0A         0A
[POWER_clamp]
|Voltage   I(typ)   I(min)   I(max)
-1.35V    95.95mA    98.77mA    98.17mA
-1.226V   73.77mA    77mA       75.43mA
-1.17V    65.26mA    68.42mA    66.73mA
-1.114V   58.22mA    60.99mA    59.66mA
-1.058V   52.94mA    54.96mA    54.53mA
-974mV    47.8mA     48.54mA    49.6mA
-806mV    41.17mA    40.91mA    42.91mA
-470mV    30.68mA    30.63mA    31.8mA
118mV     16.68mA    16.02mA    17.83mA
650mV     989uA      0A         2.418mA
734mV     0A         0A         0A
1.35V     0A         0A         0A
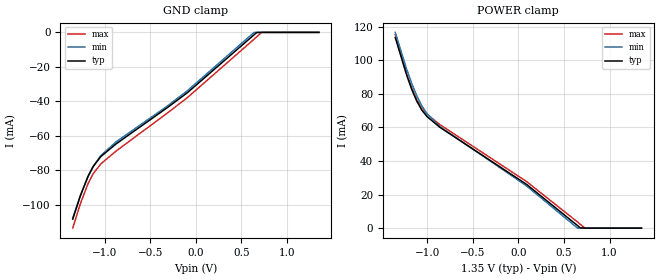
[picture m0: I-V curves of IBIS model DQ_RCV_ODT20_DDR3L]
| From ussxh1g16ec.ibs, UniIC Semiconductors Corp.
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|   Model DQ_RCV_ODT20_DDR3L
[Model] DQ_RCV_ODT20_DDR3L
Model_type Input
Vinl =  0.540V
Vinh =  0.810V
C_comp   1.224pF   1.223pF   1.239pF
[Model Spec]
Vinh   0.810V   0.776V   0.860V
Vinl   0.540V   0.506V   0.590V
[Temperature Range]   25.000   95.000   0.0
[Voltage Range]   1.350V   1.283V   1.450V
[GND_clamp]
|Voltage   I(typ)   I(min)   I(max)
-1.35V    -108.2mA   -107.6mA   -113.4mA
-1.266V   -94.53mA   -94.53mA   -99.18mA
-1.182V   -83.3mA    -83.54mA   -87.56mA
-1.126V   -77.67mA   -77.74mA   -81.86mA
-1.042V   -71.93mA   -71.35mA   -76.17mA
-874mV    -64.56mA   -63.38mA   -68.71mA
-314mV    -43.64mA   -42.72mA   -46.8mA
-90mV     -34.81mA   -33.68mA   -37.66mA
638mV     -1.428mA   -37.85uA   -3.977mA
666mV     -111.2uA   0A         -2.657mA
722mV     0A         0A         -22.99uA
1.35V     0A         0A         0A
[POWER_clamp]
|Voltage   I(typ)   I(min)   I(max)
-1.35V    113.5mA    116.6mA    115.3mA
-1.226V   91.28mA    94.86mA    92.52mA
-1.17V    82.71mA    86.29mA    83.77mA
-1.114V   75.61mA    78.86mA    76.65mA
-1.058V   70.25mA    72.8mA     71.47mA
-1.002V   66.46mA    68.15mA    67.88mA
-862mV    60.12mA    60.54mA    61.72mA
90mV      26.06mA    25.13mA    27.75mA
650mV     1.484mA    0A         3.622mA
678mV     170.7uA    0A         2.317mA
734mV     0A         0A         0A
1.35V     0A         0A         0A
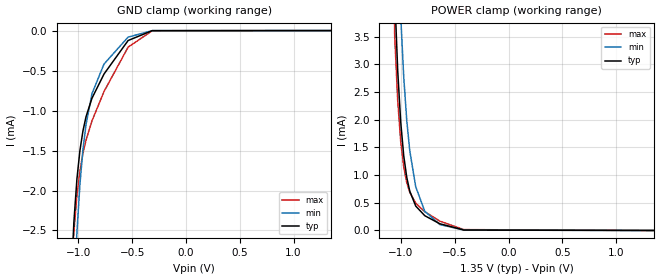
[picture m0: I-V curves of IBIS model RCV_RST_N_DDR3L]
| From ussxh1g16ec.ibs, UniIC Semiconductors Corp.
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|   Model RCV_RST_N_DDR3L
[Model] RCV_RST_N_DDR3L
Model_type Input
Vinl =  0.540V
Vinh =  0.810V
C_comp   0.822pF   0.822pF   0.822pF
[Model Spec]
Vinh   0.810V   0.776V   0.860V
Vinl   0.540V   0.506V   0.590V
[Temperature Range]   25.000   95.000   0.0
[Voltage Range]   1.350V   1.283V   1.450V
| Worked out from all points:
|   GND clamp passes 1 mA (typ) near -0.91 V on its own axis
|   POWER clamp passes 1 mA (typ) near -0.95 V on its own axis
[GND_clamp]
|Voltage   I(typ)   I(min)   I(max)
-1.35V    -37.62mA   -38.78mA   -37.97mA
-1.07V    -3.19mA    -4.506mA   -3.214mA
-1.042V   -2.392mA   -3.366mA   -2.519mA
-1.014V   -1.858mA   -2.528mA   -2.062mA
-986mV    -1.5mA     -1.923mA   -1.754mA
-958mV    -1.256mA   -1.49mA    -1.537mA
-930mV    -1.081mA   -1.179mA   -1.373mA
-874mV    -846uA     -789uA     -1.129mA
-762mV    -543uA     -418.3uA   -761.9uA
-538mV    -124.2uA   -81.69uA   -207.1uA
-314mV    -814.5nA   -860.9nA   -2.168uA
1.35V     0A         0A         0A
[POWER_clamp]
|Voltage   I(typ)   I(min)   I(max)
-1.35V    52.57mA    56.18mA    51.8mA
-1.058V   4.281mA    7.376mA    3.516mA
-1.03V    2.891mA    5.384mA    2.35mA
-1.002V   1.959mA    3.878mA    1.608mA
-974mV    1.352mA    2.777mA    1.149mA
-946mV    961.9uA    1.993mA    865.9uA
-918mV    711.2uA    1.443mA    689.3uA
-862mV    439.9uA    786.1uA    493.6uA
-778mV    266.6uA    346.5uA    338.6uA
-638mV    121.1uA    107.1uA    168.5uA
-414mV    7.521uA    6.899uA    15.19uA
1.35V     0A         0A         0A
